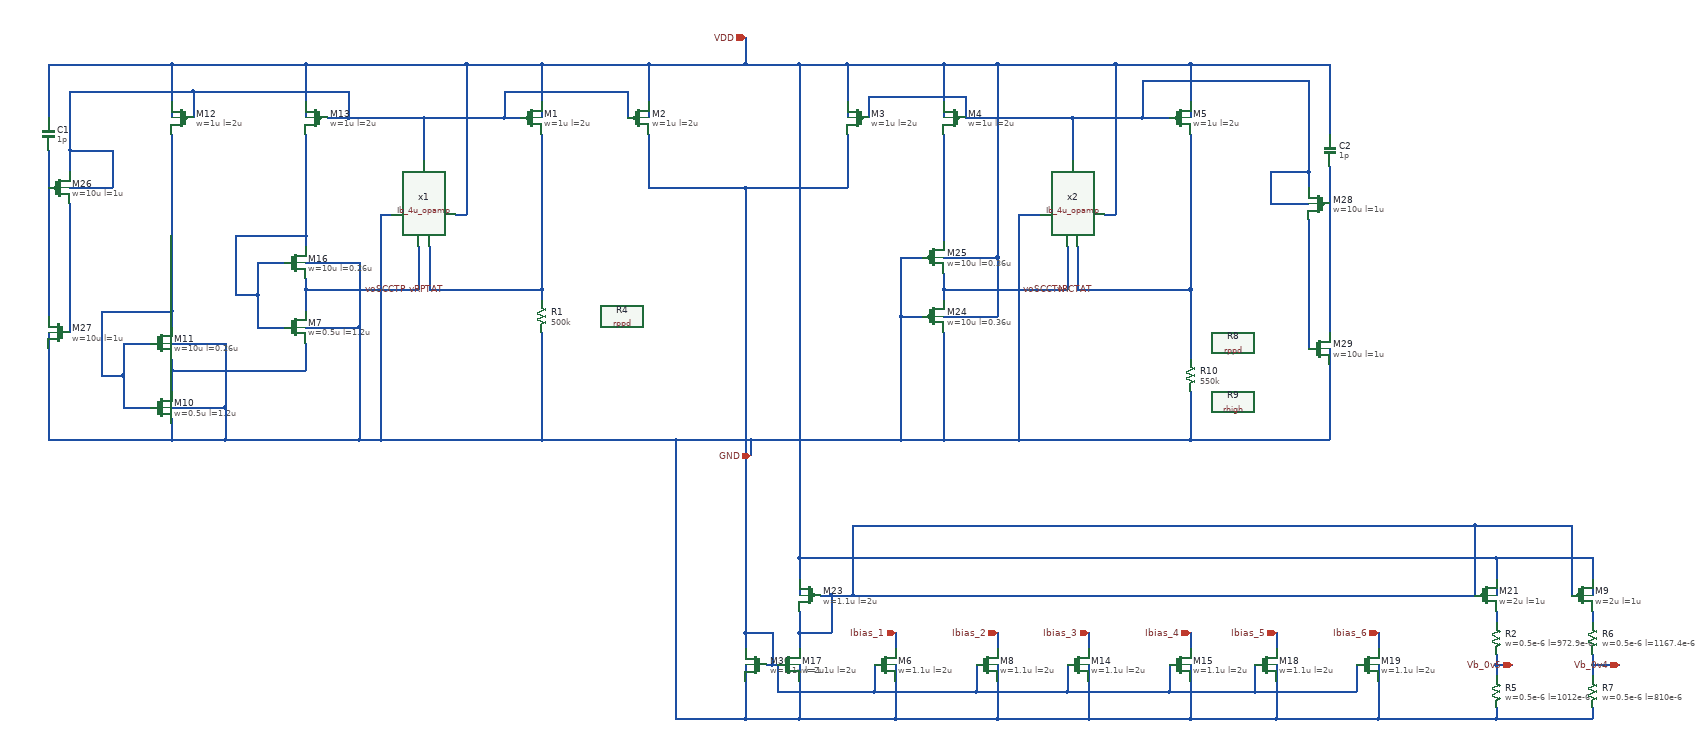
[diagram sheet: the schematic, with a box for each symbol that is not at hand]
v {xschem version=3.4.6 file_version=1.2}
G {}
K {}
V {}
S {}
E {}
N 1770 -1030 1770 -990 {lab=#net1}
N 1650 -730 1690 -730 {lab=GND}
N 1650 -620 1690 -620 {lab=GND}
N 1730 -670 1730 -650 {lab=voSCCTN}
N 2100 -990 2150 -990 {lab=#net1}
N 1180 -1090 1180 -990 {lab=VDD}
N 1550 -1090 1550 -990 {lab=VDD}
N 290 -1090 540 -1090 {lab=VDD}
N 980 -1090 980 -990 {lab=VDD}
N 840 -1090 980 -1090 {lab=VDD}
N 910 -990 940 -990 {lab=#net2}
N 910 -1040 910 -990 {lab=#net2}
N 1140 -1040 1140 -990 {lab=#net2}
N 1590 -1030 1590 -990 {lab=#net1}
N 540 -1090 540 -990 {lab=VDD}
N 820 -810 840 -810 {lab=VDD}
N 840 -1090 840 -810 {lab=VDD}
N 540 -1090 840 -1090 {lab=VDD}
N 540 -670 540 -630 {lab=voSCCTP}
N 540 -720 640 -720 {lab=GND}
N 640 -720 640 -600 {lab=GND}
N 540 -600 640 -600 {lab=GND}
N 450 -720 500 -720 {lab=#net3}
N 450 -660 450 -600 {lab=#net3}
N 450 -600 500 -600 {lab=#net3}
N 540 -770 540 -750 {lab=#net3}
N 410 -660 450 -660 {lab=#net3}
N 450 -720 450 -660 {lab=#net3}
N 410 -770 410 -660 {lab=#net3}
N 410 -770 540 -770 {lab=#net3}
N 540 -960 540 -770 {lab=#net3}
N 540 -670 750 -670 {lab=voSCCTP}
N 540 -690 540 -670 {lab=voSCCTP}
N 750 -750 750 -670 {lab=voSCCTP}
N 290 -520 290 -480 {lab=#net4}
N 290 -570 390 -570 {lab=GND}
N 390 -570 390 -450 {lab=GND}
N 290 -450 390 -450 {lab=GND}
N 200 -570 250 -570 {lab=#net5}
N 200 -510 200 -450 {lab=#net5}
N 200 -450 250 -450 {lab=#net5}
N 160 -510 200 -510 {lab=#net5}
N 200 -570 200 -510 {lab=#net5}
N 290 -520 540 -520 {lab=#net4}
N 290 -540 290 -520 {lab=#net4}
N 540 -570 540 -520 {lab=#net4}
N 290 -630 290 -600 {lab=#net5}
N 330 -1040 620 -1040 {lab=#net2}
N 620 -1040 620 -990 {lab=#net2}
N 580 -990 620 -990 {lab=#net2}
N 290 -430 290 -390 {lab=GND}
N 160 -630 160 -510 {lab=#net5}
N 160 -630 290 -630 {lab=#net5}
N 290 -960 290 -630 {lab=#net5}
N 1650 -730 1650 -620 {lab=GND}
N 640 -600 640 -390 {lab=GND}
N 390 -390 640 -390 {lab=GND}
N 390 -450 390 -390 {lab=GND}
N 290 -390 390 -390 {lab=GND}
N 2050 -1090 2190 -1090 {lab=VDD}
N 980 -670 980 -650 {lab=vRPTAT}
N 980 -590 980 -390 {lab=GND}
N 680 -390 980 -390 {lab=GND}
N 770 -750 770 -670 {lab=vRPTAT}
N 770 -670 980 -670 {lab=vRPTAT}
N 980 -960 980 -670 {lab=vRPTAT}
N 2190 -670 2190 -540 {lab=vRCTAT}
N 2190 -960 2190 -670 {lab=vRCTAT}
N 1730 -960 1730 -760 {lab=#net6}
N 1730 -590 1730 -390 {lab=GND}
N 1730 -700 1730 -670 {lab=voSCCTN}
N 1870 -810 1910 -810 {lab=GND}
N 1870 -810 1870 -390 {lab=GND}
N 1730 -390 1870 -390 {lab=GND}
N 2030 -810 2050 -810 {lab=VDD}
N 2050 -1090 2050 -810 {lab=VDD}
N 1830 -1090 2050 -1090 {lab=VDD}
N 1650 -390 1730 -390 {lab=GND}
N 1650 -620 1650 -390 {lab=GND}
N 980 -1090 1180 -1090 {lab=VDD}
N 1730 -1090 1830 -1090 {lab=VDD}
N 1460 -1090 1550 -1090 {lab=VDD}
N 680 -810 700 -810 {lab=GND}
N 680 -810 680 -390 {lab=GND}
N 1180 -960 1180 -860 {lab=#net7}
N 1550 -960 1550 -860 {lab=#net7}
N 1360 -1140 1360 -1090 {lab=VDD}
N 1180 -1090 1360 -1090 {lab=VDD}
N 1370 -390 1650 -390 {lab=GND}
N 1370 -390 1370 -360 {lab=GND}
N 1230 -390 1230 130 {lab=GND}
N 980 -390 1230 -390 {lab=GND}
N 1360 30 1360 130 {lab=GND}
N 1360 -30 1360 -0 {lab=#net7}
N 1410 30 1420 30 {lab=#net7}
N 1230 130 1360 130 {lab=GND}
N 1360 -1090 1460 -1090 {lab=VDD}
N 1360 -30 1410 -30 {lab=#net7}
N 1460 -30 1460 -0 {lab=#net8}
N 1360 130 1460 130 {lab=GND}
N 1460 -170 1460 -100 {lab=VDD}
N 1560 -100 2720 -100 {lab=#net8}
N 1460 30 1460 130 {lab=GND}
N 1560 -230 1560 -100 {lab=#net8}
N 1520 -100 1560 -100 {lab=#net8}
N 1460 -170 2760 -170 {lab=VDD}
N 1460 -30 1520 -30 {lab=#net8}
N 1460 -70 1460 -30 {lab=#net8}
N 1520 -100 1520 -30 {lab=#net8}
N 1500 -100 1520 -100 {lab=#net8}
N 2760 -70 2760 -50 {lab=#net9}
N 2760 110 2760 130 {lab=GND}
N 2760 30 2760 50 {lab=Vb_0v5}
N 2760 30 2790 30 {lab=Vb_0v5}
N 2760 10 2760 30 {lab=Vb_0v5}
N 2940 -70 2940 -50 {lab=#net10}
N 2940 30 2940 50 {lab=Vb_0v4}
N 2760 130 2940 130 {lab=GND}
N 2940 110 2940 130 {lab=GND}
N 2940 30 2990 30 {lab=Vb_0v4}
N 2940 10 2940 30 {lab=Vb_0v4}
N 2760 -170 2940 -170 {lab=VDD}
N 2540 130 2760 130 {lab=GND}
N 2940 -170 2940 -100 {lab=VDD}
N 2720 -230 2720 -100 {lab=#net8}
N 2720 -230 2900 -230 {lab=#net8}
N 2900 -230 2900 -100 {lab=#net8}
N 2760 -170 2760 -100 {lab=VDD}
N 640 -390 680 -390 {lab=GND}
N 1870 -390 2190 -390 {lab=GND}
N 1560 -230 2720 -230 {lab=#net8}
N 290 -1090 290 -990 {lab=VDD}
N 330 -1040 330 -990 {lab=#net2}
N 1410 -30 1410 30 {lab=#net7}
N 1400 30 1410 30 {lab=#net7}
N 1360 -860 1550 -860 {lab=#net7}
N 1230 -390 1370 -390 {lab=GND}
N 1460 -1090 1460 -170 {lab=VDD}
N 910 -1040 1140 -1040 {lab=#net2}
N 1590 -1030 1770 -1030 {lab=#net1}
N 1360 -860 1360 -30 {lab=#net7}
N 1180 -860 1360 -860 {lab=#net7}
N 760 -990 910 -990 {lab=#net2}
N 1970 -990 1970 -910 {lab=#net1}
N 1770 -990 1970 -990 {lab=#net1}
N 760 -990 760 -910 {lab=#net2}
N 620 -990 760 -990 {lab=#net2}
N 2190 -480 2190 -390 {lab=GND}
N 1980 -750 1980 -670 {lab=vRCTAT}
N 1960 -750 1960 -670 {lab=voSCCTN}
N 1980 -670 2190 -670 {lab=vRCTAT}
N 1730 -1090 1730 -990 {lab=VDD}
N 1550 -1090 1730 -1090 {lab=VDD}
N 2190 -1090 2190 -990 {lab=VDD}
N 1730 -670 1960 -670 {lab=voSCCTN}
N 1730 -730 1830 -730 {lab=VDD}
N 1830 -1090 1830 -730 {lab=VDD}
N 1830 -730 1830 -620 {lab=VDD}
N 1730 -620 1830 -620 {lab=VDD}
N 60 -590 60 -390 {lab=GND}
N 60 -930 60 -620 {lab=#net11}
N 100 -930 100 -890 {lab=#net2}
N 2450 -560 2450 -390 {lab=GND}
N 2450 -900 2450 -590 {lab=#net12}
N 2450 -1090 2450 -960 {lab=VDD}
N 2410 -890 2410 -860 {lab=#net1}
N 2190 -390 2450 -390 {lab=GND}
N 60 -390 290 -390 {lab=GND}
N 100 -830 100 -590 {lab=#net13}
N 100 -860 180 -860 {lab=#net2}
N 180 -930 180 -860 {lab=#net2}
N 100 -930 180 -930 {lab=#net2}
N 60 -1090 60 -990 {lab=VDD}
N 60 -1090 290 -1090 {lab=VDD}
N 100 -1040 100 -930 {lab=#net2}
N 2410 -800 2410 -560 {lab=#net14}
N 2340 -830 2410 -830 {lab=#net1}
N 2340 -890 2340 -830 {lab=#net1}
N 2340 -890 2410 -890 {lab=#net1}
N 2190 -1090 2450 -1090 {lab=VDD}
N 2100 -1060 2100 -990 {lab=#net1}
N 1970 -990 2100 -990 {lab=#net1}
N 2410 -1060 2410 -890 {lab=#net1}
N 100 -1040 330 -1040 {lab=#net2}
N 2100 -1060 2410 -1060 {lab=#net1}
N 1640 -30 1640 -0 {lab=Ibias_1}
N 1460 130 1640 130 {lab=GND}
N 2000 -30 2000 0 {lab=Ibias_3}
N 1830 -30 1830 -0 {lab=Ibias_2}
N 2190 -30 2190 0 {lab=Ibias_4}
N 2350 -30 2350 -0 {lab=Ibias_5}
N 2540 -30 2540 0 {lab=Ibias_6}
N 1640 130 1830 130 {lab=GND}
N 1830 30 1830 130 {lab=GND}
N 1640 30 1640 130 {lab=GND}
N 1830 130 2000 130 {lab=GND}
N 2000 30 2000 130 {lab=GND}
N 2000 130 2190 130 {lab=GND}
N 2190 30 2190 130 {lab=GND}
N 2190 130 2350 130 {lab=GND}
N 2350 30 2350 130 {lab=GND}
N 2350 130 2540 130 {lab=GND}
N 2540 30 2540 130 {lab=GND}
N 1420 30 1420 80 {lab=#net7}
N 2310 80 2500 80 {lab=#net7}
N 2500 30 2500 80 {lab=#net7}
N 2310 30 2310 80 {lab=#net7}
N 2150 80 2310 80 {lab=#net7}
N 2150 30 2150 80 {lab=#net7}
N 1960 80 2150 80 {lab=#net7}
N 1960 30 1960 80 {lab=#net7}
N 1790 80 1960 80 {lab=#net7}
N 1790 30 1790 80 {lab=#net7}
N 1600 80 1790 80 {lab=#net7}
N 1600 30 1600 80 {lab=#net7}
N 1420 80 1600 80 {lab=#net7}
C {iopin.sym} 1360 -1140 0 0 {name=p1 lab=VDD}
C {iopin.sym} 1370 -360 0 0 {name=p2 lab=GND}
C {iopin.sym} 1640 -30 0 0 {name=p3 lab=Ibias_1}
C {lab_pin.sym} 730 -670 3 0 {name=p9 sig_type=std_logic lab=voSCCTP}
C {lab_pin.sym} 1960 -670 3 0 {name=p10 sig_type=std_logic lab=voSCCTN}
C {lab_pin.sym} 2010 -670 3 0 {name=p11 sig_type=std_logic lab=vRCTAT}
C {lab_pin.sym} 800 -670 3 0 {name=p12 sig_type=std_logic lab=vRPTAT}
C {sg13g2_pr/sg13_lv_pmos.sym} 960 -990 0 0 {name=M1
l=2u
w=1u
ng=1
m=1
model=sg13_lv_pmos
spiceprefix=X
}
C {sg13g2_pr/sg13_lv_pmos.sym} 1160 -990 0 0 {name=M2
l=2u
w=1u
ng=1
m=6
model=sg13_lv_pmos
spiceprefix=X
}
C {sg13g2_pr/sg13_lv_pmos.sym} 1570 -990 0 1 {name=M3
l=2u
w=1u
ng=1
m=6
model=sg13_lv_pmos
spiceprefix=X
}
C {sg13g2_pr/sg13_lv_pmos.sym} 1750 -990 0 1 {name=M4
l=2u
w=1u
ng=1
m=1
model=sg13_lv_pmos
spiceprefix=X
}
C {sg13g2_pr/sg13_lv_pmos.sym} 310 -990 0 1 {name=M12
l=2u
w=1u
ng=1
m=1
model=sg13_lv_pmos
spiceprefix=X
}
C {sg13g2_pr/sg13_lv_pmos.sym} 560 -990 0 1 {name=M13
l=2u
w=1u
ng=1
m=1
model=sg13_lv_pmos
spiceprefix=X
}
C {sg13g2_pr/sg13_lv_pmos.sym} 2170 -990 0 0 {name=M5
l=2u
w=1u
ng=1
m=1
model=sg13_lv_pmos
spiceprefix=X
}
C {sg13g2_pr/sg13_lv_nmos.sym} 520 -600 0 0 {name=M7
l=1.2u
w=0.5u
ng=1
m=1
model=sg13_lv_nmos
spiceprefix=X
}
C {sg13g2_pr/sg13_lv_nmos.sym} 270 -450 0 0 {name=M10
l=1.2u
w=0.5u
ng=1
m=1
model=sg13_lv_nmos
spiceprefix=X
}
C {sg13g2_pr/sg13_lv_nmos.sym} 270 -570 0 0 {name=M11
l=0.26u
w=10u
ng=1
m=20
model=sg13_lv_nmos
spiceprefix=X
}
C {sg13g2_pr/sg13_lv_nmos.sym} 520 -720 0 0 {name=M16
l=0.26u
w=10u
ng=1
m=20
model=sg13_lv_nmos
spiceprefix=X
}
C {iopin.sym} 1830 -30 0 0 {name=p4 lab=Ibias_2}
C {iopin.sym} 2000 -30 0 0 {name=p5 lab=Ibias_3}
C {iopin.sym} 2190 -30 0 0 {name=p6 lab=Ibias_4}
C {iopin.sym} 2350 -30 0 0 {name=p7 lab=Ibias_5}
C {iopin.sym} 2540 -30 0 0 {name=p8 lab=Ibias_6}
C {/shared/designs/SSDOR_w_startup_1V_ihp/Ib_4u/Ib_4u_opamp/Ib_4u_opamp.sym} 700 -750 1 1 {name=x1}
C {/shared/designs/SSDOR_w_startup_1V_ihp/Ib_4u/Ib_4u_opamp/Ib_4u_opamp.sym} 1910 -750 1 1 {name=x2}
C {sg13g2_pr/sg13_lv_nmos.sym} 1380 30 0 1 {name=M30
l=2u
w=1.1u
ng=1
m=3
model=sg13_lv_nmos
spiceprefix=X
}
C {sg13g2_pr/rppd.sym} 2760 -20 0 0 {name=R2
w=0.5e-6
l=972.9e-6
model=rppd
body=GND
spiceprefix=X
b=0
m=1
}
C {sg13g2_pr/rppd.sym} 2940 -20 0 0 {name=R6
w=0.5e-6
l=1167.4e-6
model=rppd
body=GND
spiceprefix=X
b=0
m=1
}
C {sg13g2_pr/rppd.sym} 2940 80 0 0 {name=R7
w=0.5e-6
l=810e-6
model=rppd
body=GND
spiceprefix=X
b=0
m=1
}
C {iopin.sym} 2990 30 0 0 {name=p16 lab=Vb_0v4}
C {iopin.sym} 2790 30 0 0 {name=p17 lab=Vb_0v5}
C {sg13g2_pr/rppd.sym} 2760 80 0 0 {name=R5
w=0.5e-6
l=1012e-6
model=rppd
body=GND
spiceprefix=X
b=0
m=1
}
C {sg13g2_pr/sg13_lv_nmos.sym} 1440 30 0 0 {name=M17
l=2u
w=1.1u
ng=1
m=3
model=sg13_lv_nmos
spiceprefix=X
}
C {sg13g2_pr/sg13_lv_pmos.sym} 2740 -100 0 0 {name=M21
l=1u
w=2u
ng=1
m=1
model=sg13_lv_pmos
spiceprefix=X
}
C {sg13g2_pr/sg13_lv_pmos.sym} 2920 -100 0 0 {name=M9
l=1u
w=2u
ng=1
m=1
model=sg13_lv_pmos
spiceprefix=X
}
C {sg13g2_pr/sg13_lv_pmos.sym} 1480 -100 0 1 {name=M23
l=2u
w=1.1u
ng=1
m=6
model=sg13_lv_pmos
spiceprefix=X
}
C {sg13g2_pr/rppd.sym} 1130 -620 0 0 {name=R4
w=0.5e-6
l=1940e-6
model=rppd
body=GND
spiceprefix=X
b=0
m=1
}
C {sg13g2_pr/rppd.sym} 2270 -570 0 0 {name=R8
w=0.5e-6
l=1169e-6
model=rppd
body=GND
spiceprefix=X
b=0
m=1
}
C {sg13g2_pr/rhigh.sym} 2270 -460 0 0 {name=R9
w=0.5e-6
l=27e-6
model=rhigh
body=GND
spiceprefix=X
b=0
m=1
}
C {sg13g2_pr/sg13_lv_pmos.sym} 1710 -620 0 0 {name=M24
l=0.36u
w=10u
ng=1
m=60
model=sg13_lv_pmos
spiceprefix=X
}
C {sg13g2_pr/sg13_lv_pmos.sym} 1710 -730 0 0 {name=M25
l=0.36u
w=10u
ng=1
m=1
model=sg13_lv_pmos
spiceprefix=X
}
C {res.sym} 980 -620 0 0 {name=R1
value=500k
footprint=1206
device=resistor
m=1}
C {res.sym} 2190 -510 0 0 {name=R10
value=550k
footprint=1206
device=resistor
m=1}
C {sg13g2_pr/sg13_lv_pmos.sym} 80 -860 0 0 {name=M26
l=1u
w=10u
ng=1
m=1
model=sg13_lv_nmos
spiceprefix=X
}
C {sg13g2_pr/sg13_lv_nmos.sym} 80 -590 0 1 {name=M27
l=1u
w=10u
ng=1
m=1
model=sg13_lv_nmos
spiceprefix=X
}
C {capa.sym} 60 -960 0 0 {name=C1
m=1
value=1p
footprint=1206
device="ceramic capacitor"}
C {sg13g2_pr/sg13_lv_pmos.sym} 2430 -830 0 1 {name=M28
l=1u
w=10u
ng=1
m=1
model=sg13_lv_nmos
spiceprefix=X
}
C {sg13g2_pr/sg13_lv_nmos.sym} 2430 -560 0 0 {name=M29
l=1u
w=10u
ng=1
m=1
model=sg13_lv_nmos
spiceprefix=X
}
C {capa.sym} 2450 -930 0 1 {name=C2
m=1
value=1p
footprint=1206
device="ceramic capacitor"}
C {sg13g2_pr/sg13_lv_nmos.sym} 1620 30 0 0 {name=M6
l=2u
w=1.1u
ng=1
m=3
model=sg13_lv_nmos
spiceprefix=X
}
C {sg13g2_pr/sg13_lv_nmos.sym} 1810 30 0 0 {name=M8
l=2u
w=1.1u
ng=1
m=3
model=sg13_lv_nmos
spiceprefix=X
}
C {sg13g2_pr/sg13_lv_nmos.sym} 1980 30 0 0 {name=M14
l=2u
w=1.1u
ng=1
m=3
model=sg13_lv_nmos
spiceprefix=X
}
C {sg13g2_pr/sg13_lv_nmos.sym} 2170 30 0 0 {name=M15
l=2u
w=1.1u
ng=1
m=3
model=sg13_lv_nmos
spiceprefix=X
}
C {sg13g2_pr/sg13_lv_nmos.sym} 2330 30 0 0 {name=M18
l=2u
w=1.1u
ng=1
m=3
model=sg13_lv_nmos
spiceprefix=X
}
C {sg13g2_pr/sg13_lv_nmos.sym} 2520 30 0 0 {name=M19
l=2u
w=1.1u
ng=1
m=3
model=sg13_lv_nmos
spiceprefix=X
}
